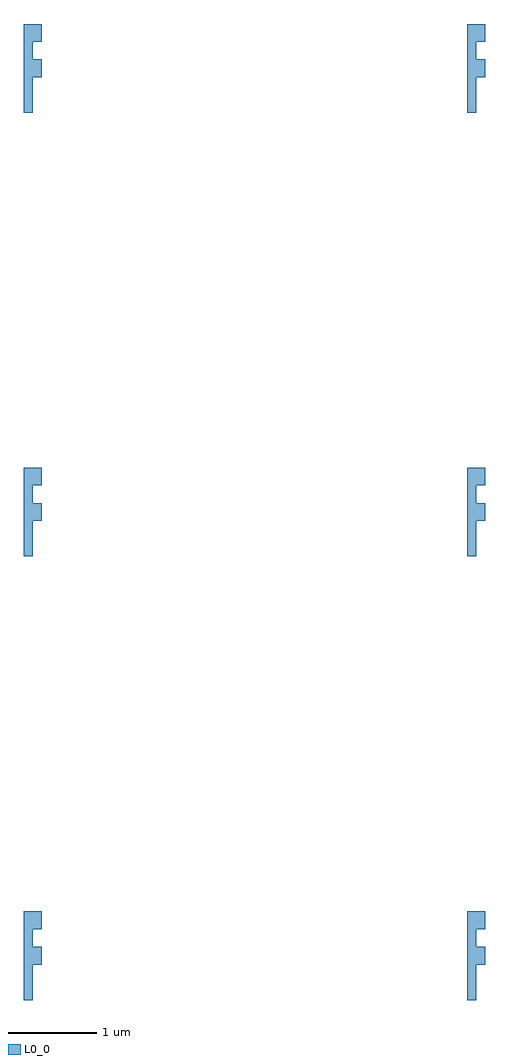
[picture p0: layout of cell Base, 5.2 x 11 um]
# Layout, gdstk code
import gdstk
lib = gdstk.Library(unit=1e-6, precision=1e-09)
def P(c, l, *ps):  # polygons
    for p in ps: c.add(gdstk.Polygon(p, *l))
L0_0 = (0, 0)

base = lib.new_cell('Base')
P(base, L0_0, [(0,0),(0,1),(0.2,1),(0.2,0.8),(0.1,0.8),(0.1,0.6),(0.2,0.6),(0.2,0.4),(0.1,0.4),(0.1,0)],
  [(5,0),(5,1),(5.2,1),(5.2,0.8),(5.1,0.8),(5.1,0.6),(5.2,0.6),(5.2,0.4),(5.1,0.4),(5.1,0)],
  [(0,5),(0,6),(0.2,6),(0.2,5.8),(0.1,5.8),(0.1,5.6),(0.2,5.6),(0.2,5.4),(0.1,5.4),(0.1,5)],
  [(5,5),(5,6),(5.2,6),(5.2,5.8),(5.1,5.8),(5.1,5.6),(5.2,5.6),(5.2,5.4),(5.1,5.4),(5.1,5)],
  [(0,10),(0,11),(0.2,11),(0.2,10.8),(0.1,10.8),(0.1,10.6),(0.2,10.6),(0.2,10.4),(0.1,10.4),(0.1,10)],
  [(5,10),(5,11),(5.2,11),(5.2,10.8),(5.1,10.8),(5.1,10.6),(5.2,10.6),(5.2,10.4),(5.1,10.4),(5.1,10)])

lib.write_gds('Base.gds')
